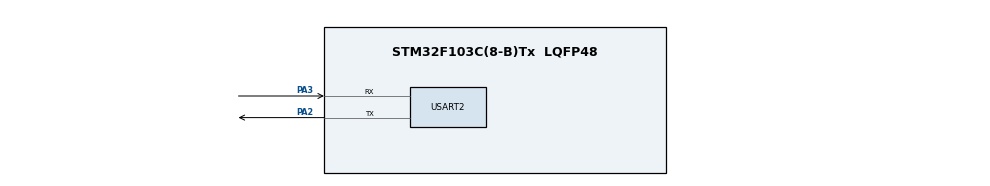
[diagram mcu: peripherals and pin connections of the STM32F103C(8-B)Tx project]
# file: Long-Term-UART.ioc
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Dma.Request0=USART2_RX
Dma.Request1=USART2_TX
Dma.USART2_RX.0.Direction=DMA_PERIPH_TO_MEMORY
Dma.USART2_RX.0.Instance=DMA1_Channel6
Dma.USART2_RX.0.MemDataAlignment=DMA_MDATAALIGN_BYTE
Dma.USART2_RX.0.MemInc=DMA_MINC_ENABLE
Dma.USART2_RX.0.Mode=DMA_NORMAL
Dma.USART2_RX.0.PeriphDataAlignment=DMA_PDATAALIGN_BYTE
Dma.USART2_RX.0.PeriphInc=DMA_PINC_DISABLE
Dma.USART2_RX.0.Priority=DMA_PRIORITY_LOW
Dma.USART2_TX.1.Direction=DMA_MEMORY_TO_PERIPH
Dma.USART2_TX.1.Instance=DMA1_Channel7
Dma.USART2_TX.1.MemDataAlignment=DMA_MDATAALIGN_BYTE
Dma.USART2_TX.1.MemInc=DMA_MINC_ENABLE
Dma.USART2_TX.1.Mode=DMA_NORMAL
Dma.USART2_TX.1.PeriphDataAlignment=DMA_PDATAALIGN_BYTE
Dma.USART2_TX.1.PeriphInc=DMA_PINC_DISABLE
Dma.USART2_TX.1.Priority=DMA_PRIORITY_LOW
Mcu.Family=STM32F1
Mcu.Name=STM32F103C(8-B)Tx
Mcu.Package=LQFP48
NVIC.DMA1_Channel6_IRQn=true\:0\:0\:false\:false\:true\:false\:true\:true
NVIC.DMA1_Channel7_IRQn=true\:0\:0\:false\:false\:true\:false\:true\:true
NVIC.PriorityGroup=NVIC_PRIORITYGROUP_4
NVIC.USART2_IRQn=true\:0\:0\:false\:false\:true\:false\:true\:true
PA13.Mode=Serial_Wire
PA13.Signal=SYS_JTMS-SWDIO
PA14.Mode=Serial_Wire
PA14.Signal=SYS_JTCK-SWCLK
PA2.Mode=Asynchronous
PA2.Signal=USART2_TX
PA3.Mode=Asynchronous
PA3.Signal=USART2_RX
PD0-OSC_IN.Mode=HSE-External-Oscillator
PD0-OSC_IN.Signal=RCC_OSC_IN
PD1-OSC_OUT.Mode=HSE-External-Oscillator
PD1-OSC_OUT.Signal=RCC_OSC_OUT
ProjectManager.HeapSize=0x200
ProjectManager.StackSize=0x400
ProjectManager.TargetToolchain=CMake
RCC.AHBFreq_Value=72000000
RCC.APB1CLKDivider=RCC_HCLK_DIV2
RCC.APB1Freq_Value=36000000
RCC.APB1TimFreq_Value=72000000
RCC.APB2Freq_Value=72000000
RCC.APB2TimFreq_Value=72000000
RCC.HCLKFreq_Value=72000000
RCC.PLLMUL=RCC_PLL_MUL9
RCC.PLLSourceVirtual=RCC_PLLSOURCE_HSE
RCC.SYSCLKFreq_VALUE=72000000
RCC.SYSCLKSource=RCC_SYSCLKSOURCE_PLLCLK
RCC.USBFreq_Value=72000000
USART2.VirtualMode=VM_ASYNC
board=custom

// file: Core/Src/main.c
/* USER CODE BEGIN Header */
/**
  ******************************************************************************
  * @file           : main.c
  * @brief          : Main program body
  ******************************************************************************
  * @attention
  *
  * Copyright (c) 2026 STMicroelectronics.
  * All rights reserved.
  *
  * This software is licensed under terms that can be found in the LICENSE file
  * in the root directory of this software component.
  * If no LICENSE file comes with this software, it is provided AS-IS.
  *
  ******************************************************************************
  */
/* USER CODE END Header */
#include "main.h"
#include "dma.h"
#include "usart.h"
#include "gpio.h"

/* USER CODE BEGIN PD */
uint8_t message[100];
/* USER CODE END PD */

void SystemClock_Config(void);
/* USER CODE BEGIN PFP */
void HAL_UARTEx_RxEventCallback(UART_HandleTypeDef *huart, uint16_t Size){
  if(huart == &huart2){
    HAL_UART_Transmit_DMA(&huart2, message, Size);
    HAL_UARTEx_ReceiveToIdle_DMA(&huart2, message, sizeof(message));
  }
}
/* USER CODE END PFP */

int main(void)
{

  /* MCU Configuration--------------------------------------------------------*/

  /* Reset of all peripherals, Initializes the Flash interface and the Systick. */
  HAL_Init();

  /* Configure the system clock */
  SystemClock_Config();

  /* Initialize all configured peripherals */
  MX_GPIO_Init();
  MX_DMA_Init();
  MX_USART2_UART_Init();
  /* USER CODE BEGIN 2 */
  HAL_UARTEx_ReceiveToIdle_DMA(&huart2, message, sizeof(message));
  /* USER CODE END 2 */

  /* Infinite loop */
  while (1)
  {

  }
}

void SystemClock_Config(void)
{
  RCC_OscInitTypeDef RCC_OscInitStruct = {0};
  RCC_ClkInitTypeDef RCC_ClkInitStruct = {0};

  /** Initializes the RCC Oscillators according to the specified parameters
  * in the RCC_OscInitTypeDef structure.
  */
  RCC_OscInitStruct.OscillatorType = RCC_OSCILLATORTYPE_HSI;
  RCC_OscInitStruct.HSIState = RCC_HSI_ON;
  RCC_OscInitStruct.HSICalibrationValue = RCC_HSICALIBRATION_DEFAULT;
  RCC_OscInitStruct.PLL.PLLState = RCC_PLL_NONE;
  if (HAL_RCC_OscConfig(&RCC_OscInitStruct) != HAL_OK)
  {
    Error_Handler();
  }

  /** Initializes the CPU, AHB and APB buses clocks
  */
  RCC_ClkInitStruct.ClockType = RCC_CLOCKTYPE_HCLK|RCC_CLOCKTYPE_SYSCLK
                              |RCC_CLOCKTYPE_PCLK1|RCC_CLOCKTYPE_PCLK2;
  RCC_ClkInitStruct.SYSCLKSource = RCC_SYSCLKSOURCE_HSI;
  RCC_ClkInitStruct.AHBCLKDivider = RCC_SYSCLK_DIV1;
  RCC_ClkInitStruct.APB1CLKDivider = RCC_HCLK_DIV1;
  RCC_ClkInitStruct.APB2CLKDivider = RCC_HCLK_DIV1;

  if (HAL_RCC_ClockConfig(&RCC_ClkInitStruct, FLASH_LATENCY_0) != HAL_OK)
  {
    Error_Handler();
  }
}

void Error_Handler(void)
{
  __disable_irq();
  while (1)
  {
  }
}
